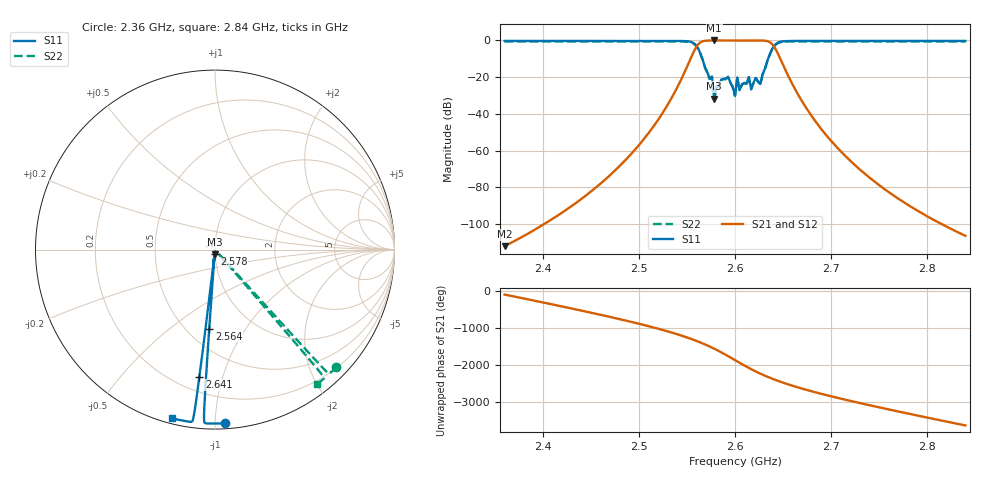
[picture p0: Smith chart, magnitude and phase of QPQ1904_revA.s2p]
! written by passband
# GHZ S DB R 50
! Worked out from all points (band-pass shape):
!   201 points, 2.36 GHz to 2.84 GHz, reference 50 ohm
!   highest |S21| = 0.00 dB at 2.578 GHz (marker M1); lowest = -112.0 dB at 2.36 GHz (marker M2)
!   |S21| within 3 dB of the highest: 2.56 GHz to 2.64 GHz (79.73 MHz wide, 3.07 % of centre)
!   lowest |S11| = -31.6 dB at 2.578 GHz (marker M3), VSWR 1.05, Z = 49.7 - j2.6 ohm
!   |S11| at or under -10 dB: 2.566 GHz to 2.634 GHz (68.47 MHz wide, 2.63 % of centre)
!   |S22| runs from -31.9 to -0.5 dB; largest |S21 - S12| = 0
!   S11 on the Smith chart (normalised r, x): 2.36 GHz: 0.03, -1.06; 2.564 GHz: 0.64, -0.70; 2.578 GHz: 0.99, -0.05; 2.641 GHz: 0.29, -0.84; 2.84 GHz: 0.02, -0.78
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2.36  -0.27 -86.7  -112.00 -104.7  -112.00 -104.7  -0.53 -44.0
2.4416  -0.27 -89.7  -85.64 173.1  -85.64 173.1  -0.53 -45.6
2.5208  -0.27 -92.6  -42.51 47.2  -42.51 47.2  -0.53 -47.0
2.5544  -0.84 -93.8  -9.10 136.8  -9.10 136.8  -1.10 -47.7
2.564  -7.10 -94.2  -1.01 41.0  -1.01 41.0  -7.36 -47.8
2.5712  -17.38 -94.4  -0.09 -39.1  -0.09 -39.1  -17.64 -48.0
2.5784  -31.63 -94.7  -0.00 -127.2  -0.00 -127.2  -31.89 -48.1
2.5832  -24.73 -94.9  -0.02 169.4  -0.02 169.4  -25.00 -48.2
2.588  -20.86 -95.1  -0.04 102.5  -0.04 102.5  -21.12 -48.3
2.5952  -22.89 -95.3  -0.02 -2.8  -0.02 -2.8  -23.15 -48.4
2.6  -30.01 -95.5  -0.00 -74.8  -0.00 -74.8  -30.28 -48.5
2.6024  -20.12 -95.6  -0.05 -110.8  -0.05 -110.8  -20.39 -48.6
2.6072  -23.88 -95.8  -0.02 177.8  -0.02 177.8  -24.14 -48.7
2.612  -23.37 -95.9  -0.02 108.4  -0.02 108.4  -23.64 -48.7
2.6192  -23.06 -96.2  -0.02 10.0  -0.02 10.0  -23.33 -48.9
2.6264  -23.67 -96.5  -0.02 -80.2  -0.02 -80.2  -23.93 -49.0
2.6336  -11.26 -96.7  -0.36 -162.2  -0.36 -162.2  -11.52 -49.1
2.6408  -2.93 -97.0  -3.39 123.2  -3.39 123.2  -3.19 -49.3
2.648  -0.63 -97.3  -10.94 55.0  -10.94 55.0  -0.90 -49.4
2.6816  -0.27 -98.5  -42.47 151.4  -42.47 151.4  -0.53 -50.0
2.7608  -0.27 -101.4  -82.83 29.7  -82.83 29.7  -0.53 -51.5
2.84  -0.27 -104.3  -106.32 -38.9  -106.32 -38.9  -0.53 -53.0
